! (c) 2009  Infineon Technologies AG, Munich
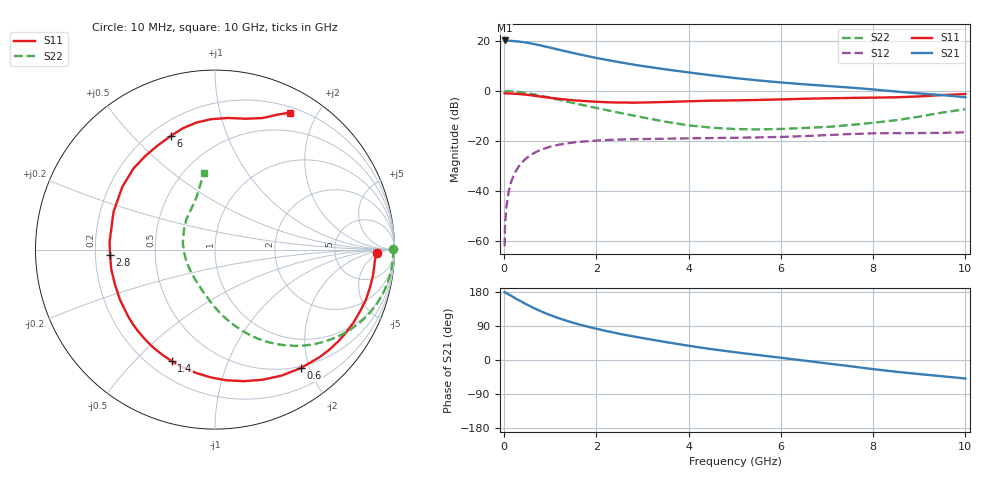
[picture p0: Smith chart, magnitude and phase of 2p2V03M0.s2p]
! Infineon Technologies  Discrete & RF Semiconductors
! BFP420
! VCE =  2.0 V,  IC =  3.0 mA
! Common Emitter S-Parameters:  Nov 2009
# GHz  S  MA  R  50
!  f  S11  S21  S12  S22
! GHz  MAG  ANG  MAG  ANG  MAG  ANG  MAG  ANG
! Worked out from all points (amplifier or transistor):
!   46 points, 10 MHz to 10 GHz, reference 50 ohm
!   highest |S21| = 20.2 dB at 10 MHz (marker M1)
!   |S21| within 3 dB of that: start of sweep to 1.028 GHz
!   unconditionally stable (mu >= 1): 3.52 GHz to end of sweep
!   at 300 MHz: K = 0.06, MSG = 25.2 dB, |S12| = -30.6 dB
!   at 1.7 GHz: K = 0.44, MSG = 17.3 dB, |S12| = -20.2 dB
!   at 10 GHz: K = 1.17, MAG = 4.5 dB, |S12| = -16.5 dB
!   lowest NFmin = 0.57 dB at 900 MHz
!   S11 on the Smith chart (normalised r, x): 10 MHz: 19, -4; 600 MHz: 0.47, -1.87; 1.4 GHz: 0.29, -0.64; 2.8 GHz: 0.26, -0.02; 6 GHz: 0.28, +0.65; 10 GHz: 0.26, +1.65
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0.01  0.902 -1.3  10.2 179.2  0.0008 112.8  0.9909 0.1
0.02  0.8966 -1.9  9.945 178.8  0.0022 86.1  0.9927 -1.1
0.05  0.8928 -4.3  9.989 176.4  0.0049 88.4  0.9927 -2.7
0.15  0.8887 -13.9  9.986 169.4  0.0152 82.3  0.9855 -8.3
0.25  0.8783 -23.1  9.814 162.3  0.0249 77.4  0.9705 -13.7
0.4  0.8564 -36.6  9.481 152.4  0.0386 70.0  0.9352 -21.5
0.6  0.8155 -54.0  8.829 139.7  0.0545 60.8  0.8729 -31.1
0.7  0.7936 -62.3  8.464 133.9  0.0613 56.6  0.8376 -35.5
0.9  0.7503 -77.7  7.693 123.3  0.0726 49.3  0.7661 -43.4
1.2  0.6952 -98.7  6.626 109.6  0.0852 40.2  0.6637 -53.5
1.4  0.6664 -111.3  6.001 101.8  0.0911 35.2  0.6035 -59.3
1.7  0.6331 -128.2  5.221 91.5  0.0978 29.1  0.5244 -66.8
1.9  0.6174 -138.4  4.77 85.3  0.1011 25.6  0.4789 -71.3
2.2  0.5983 -152.3  4.213 76.9  0.1047 21.1  0.4198 -77.5
2.8  0.5856 -177.2  3.367 62.3  0.109 14.1  0.3233 -89.8
3.5  0.6034 159.5  2.701 47.4  0.1117 8.2  0.2436 -105.9
4.5  0.6408 135.1  2.054 28.5  0.1151 2.5  0.1852 -135.3
5.5  0.662 118.8  1.627 13.2  0.1184 -1.3  0.1711 -164.0
6  0.6795 111.3  1.481 5.9  0.1211 -2.6  0.1747 -178.6
7  0.7154 98.3  1.261 -9.0  0.1317 -6.3  0.1918 156.7
8.5  0.7491 76.7  0.975 -31.0  0.144 -17.0  0.2614 120.6
10  0.8693 61.4  0.749 -48.8  0.15 -23.8  0.433 98.3
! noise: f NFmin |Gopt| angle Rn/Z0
0.9  0.57  0.35  33  0.18
1.8  1.02  0.2  79  0.14
2.4  1.1  0.23  104  0.14
3  1.25  0.24  144  0.11
4  1.46  0.33  -159  0.1
5  1.9  0.39  -128  0.22
6  2.46  0.48  -107  0.35
